VERSION 5.7 ;
  NOWIREEXTENSIONATPIN ON ;
  DIVIDERCHAR "/" ;
  BUSBITCHARS "[]" ;
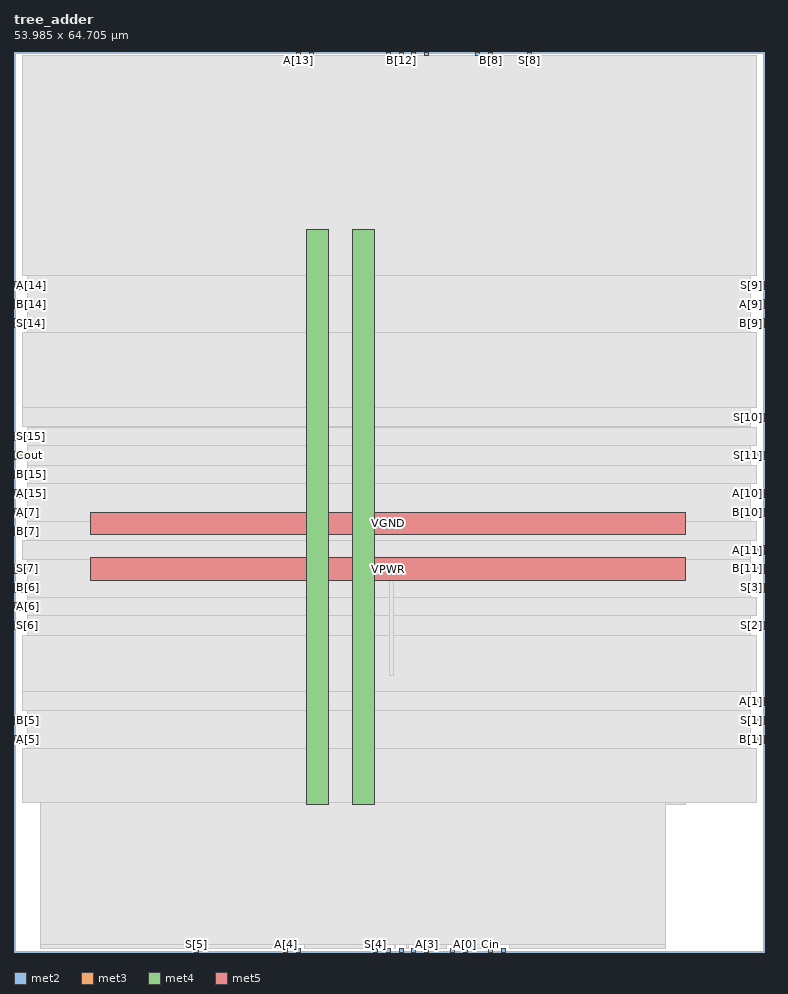
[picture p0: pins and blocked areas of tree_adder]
MACRO tree_adder
  CLASS BLOCK ;
  FOREIGN tree_adder ;
  ORIGIN 0.000 0.000 ;
  SIZE 53.985 BY 64.705 ;
  PIN A[0]
    DIRECTION INPUT ;
    USE SIGNAL ;
    ANTENNAGATEAREA 0.213000 ;
    PORT
      LAYER met2 ;
        RECT 32.290 0.000 32.570 0.280 ;
    END
  END A[0]
  PIN A[10]
    DIRECTION INPUT ;
    USE SIGNAL ;
    ANTENNAGATEAREA 0.213000 ;
    PORT
      LAYER met3 ;
        RECT 53.385 32.680 53.985 33.280 ;
    END
  END A[10]
  PIN A[11]
    DIRECTION INPUT ;
    USE SIGNAL ;
    ANTENNAGATEAREA 0.213000 ;
    PORT
      LAYER met3 ;
        RECT 53.385 28.600 53.985 29.200 ;
    END
  END A[11]
  PIN A[12]
    DIRECTION INPUT ;
    USE SIGNAL ;
    ANTENNAGATEAREA 0.213000 ;
    PORT
      LAYER met2 ;
        RECT 28.610 64.425 28.890 64.705 ;
    END
  END A[12]
  PIN A[13]
    DIRECTION INPUT ;
    USE SIGNAL ;
    ANTENNAGATEAREA 0.213000 ;
    PORT
      LAYER met2 ;
        RECT 20.330 64.425 20.610 64.705 ;
    END
  END A[13]
  PIN A[14]
    DIRECTION INPUT ;
    USE SIGNAL ;
    ANTENNAGATEAREA 0.213000 ;
    PORT
      LAYER met3 ;
        RECT 0.000 47.640 0.600 48.240 ;
    END
  END A[14]
  PIN A[15]
    DIRECTION INPUT ;
    USE SIGNAL ;
    ANTENNAGATEAREA 0.213000 ;
    PORT
      LAYER met3 ;
        RECT 0.000 32.680 0.600 33.280 ;
    END
  END A[15]
  PIN A[1]
    DIRECTION INPUT ;
    USE SIGNAL ;
    ANTENNAGATEAREA 0.213000 ;
    PORT
      LAYER met3 ;
        RECT 53.385 17.720 53.985 18.320 ;
    END
  END A[1]
  PIN A[2]
    DIRECTION INPUT ;
    USE SIGNAL ;
    ANTENNAGATEAREA 0.213000 ;
    PORT
      LAYER met2 ;
        RECT 26.770 0.000 27.050 0.280 ;
    END
  END A[2]
  PIN A[3]
    DIRECTION INPUT ;
    USE SIGNAL ;
    ANTENNAGATEAREA 0.213000 ;
    PORT
      LAYER met2 ;
        RECT 29.530 0.000 29.810 0.280 ;
    END
  END A[3]
  PIN A[4]
    DIRECTION INPUT ;
    USE SIGNAL ;
    ANTENNAGATEAREA 0.213000 ;
    PORT
      LAYER met2 ;
        RECT 19.410 0.000 19.690 0.280 ;
    END
  END A[4]
  PIN A[5]
    DIRECTION INPUT ;
    USE SIGNAL ;
    ANTENNAGATEAREA 0.213000 ;
    PORT
      LAYER met3 ;
        RECT 0.000 15.000 0.600 15.600 ;
    END
  END A[5]
  PIN A[6]
    DIRECTION INPUT ;
    USE SIGNAL ;
    ANTENNAGATEAREA 0.213000 ;
    PORT
      LAYER met3 ;
        RECT 0.000 24.520 0.600 25.120 ;
    END
  END A[6]
  PIN A[7]
    DIRECTION INPUT ;
    USE SIGNAL ;
    ANTENNAGATEAREA 0.213000 ;
    PORT
      LAYER met3 ;
        RECT 0.000 31.320 0.600 31.920 ;
    END
  END A[7]
  PIN A[8]
    DIRECTION INPUT ;
    USE SIGNAL ;
    ANTENNAGATEAREA 0.213000 ;
    PORT
      LAYER met2 ;
        RECT 33.210 64.425 33.490 64.705 ;
    END
  END A[8]
  PIN A[9]
    DIRECTION INPUT ;
    USE SIGNAL ;
    ANTENNAGATEAREA 0.213000 ;
    PORT
      LAYER met3 ;
        RECT 53.385 46.280 53.985 46.880 ;
    END
  END A[9]
  PIN B[0]
    DIRECTION INPUT ;
    USE SIGNAL ;
    ANTENNAGATEAREA 0.213000 ;
    PORT
      LAYER met2 ;
        RECT 31.370 0.000 31.650 0.280 ;
    END
  END B[0]
  PIN B[10]
    DIRECTION INPUT ;
    USE SIGNAL ;
    ANTENNAGATEAREA 0.213000 ;
    PORT
      LAYER met3 ;
        RECT 53.385 31.320 53.985 31.920 ;
    END
  END B[10]
  PIN B[11]
    DIRECTION INPUT ;
    USE SIGNAL ;
    ANTENNAGATEAREA 0.213000 ;
    PORT
      LAYER met3 ;
        RECT 53.385 27.240 53.985 27.840 ;
    END
  END B[11]
  PIN B[12]
    DIRECTION INPUT ;
    USE SIGNAL ;
    ANTENNAGATEAREA 0.213000 ;
    PORT
      LAYER met2 ;
        RECT 27.690 64.425 27.970 64.705 ;
    END
  END B[12]
  PIN B[13]
    DIRECTION INPUT ;
    USE SIGNAL ;
    ANTENNAGATEAREA 0.213000 ;
    PORT
      LAYER met2 ;
        RECT 21.250 64.400 21.530 64.705 ;
    END
  END B[13]
  PIN B[14]
    DIRECTION INPUT ;
    USE SIGNAL ;
    ANTENNAGATEAREA 0.213000 ;
    PORT
      LAYER met3 ;
        RECT 0.000 46.280 0.600 46.880 ;
    END
  END B[14]
  PIN B[15]
    DIRECTION INPUT ;
    USE SIGNAL ;
    ANTENNAGATEAREA 0.213000 ;
    PORT
      LAYER met3 ;
        RECT 0.000 34.040 0.600 34.640 ;
    END
  END B[15]
  PIN B[1]
    DIRECTION INPUT ;
    USE SIGNAL ;
    ANTENNAGATEAREA 0.213000 ;
    PORT
      LAYER met3 ;
        RECT 53.385 15.000 53.985 15.600 ;
    END
  END B[1]
  PIN B[2]
    DIRECTION INPUT ;
    USE SIGNAL ;
    ANTENNAGATEAREA 0.213000 ;
    PORT
      LAYER met2 ;
        RECT 27.690 0.000 27.970 0.280 ;
    END
  END B[2]
  PIN B[3]
    DIRECTION INPUT ;
    USE SIGNAL ;
    ANTENNAGATEAREA 0.213000 ;
    PORT
      LAYER met2 ;
        RECT 28.610 0.000 28.890 0.280 ;
    END
  END B[3]
  PIN B[4]
    DIRECTION INPUT ;
    USE SIGNAL ;
    ANTENNAGATEAREA 0.213000 ;
    PORT
      LAYER met2 ;
        RECT 20.330 0.000 20.610 0.280 ;
    END
  END B[4]
  PIN B[5]
    DIRECTION INPUT ;
    USE SIGNAL ;
    ANTENNAGATEAREA 0.213000 ;
    PORT
      LAYER met3 ;
        RECT 0.000 16.360 0.600 16.960 ;
    END
  END B[5]
  PIN B[6]
    DIRECTION INPUT ;
    USE SIGNAL ;
    ANTENNAGATEAREA 0.213000 ;
    PORT
      LAYER met3 ;
        RECT 0.000 25.880 0.600 26.480 ;
    END
  END B[6]
  PIN B[7]
    DIRECTION INPUT ;
    USE SIGNAL ;
    ANTENNAGATEAREA 0.213000 ;
    PORT
      LAYER met3 ;
        RECT 0.000 29.960 0.600 30.560 ;
    END
  END B[7]
  PIN B[8]
    DIRECTION INPUT ;
    USE SIGNAL ;
    ANTENNAGATEAREA 0.213000 ;
    PORT
      LAYER met2 ;
        RECT 34.130 64.425 34.410 64.705 ;
    END
  END B[8]
  PIN B[9]
    DIRECTION INPUT ;
    USE SIGNAL ;
    ANTENNAGATEAREA 0.213000 ;
    PORT
      LAYER met3 ;
        RECT 53.385 44.920 53.985 45.520 ;
    END
  END B[9]
  PIN Cin
    DIRECTION INPUT ;
    USE SIGNAL ;
    ANTENNAGATEAREA 0.213000 ;
    PORT
      LAYER met2 ;
        RECT 34.130 0.000 34.410 0.280 ;
    END
  END Cin
  PIN Cout
    DIRECTION OUTPUT ;
    USE SIGNAL ;
    ANTENNAGATEAREA 0.126000 ;
    ANTENNADIFFAREA 0.429000 ;
    PORT
      LAYER met3 ;
        RECT 0.000 35.400 0.600 36.000 ;
    END
  END Cout
  PIN S[0]
    DIRECTION OUTPUT ;
    USE SIGNAL ;
    ANTENNADIFFAREA 0.702900 ;
    PORT
      LAYER met2 ;
        RECT 35.050 0.000 35.330 0.280 ;
    END
  END S[0]
  PIN S[10]
    DIRECTION OUTPUT ;
    USE SIGNAL ;
    ANTENNADIFFAREA 0.702900 ;
    PORT
      LAYER met3 ;
        RECT 53.385 38.120 53.985 38.720 ;
    END
  END S[10]
  PIN S[11]
    DIRECTION OUTPUT ;
    USE SIGNAL ;
    ANTENNADIFFAREA 0.383400 ;
    PORT
      LAYER met3 ;
        RECT 53.385 35.400 53.985 36.000 ;
    END
  END S[11]
  PIN S[12]
    DIRECTION OUTPUT ;
    USE SIGNAL ;
    ANTENNADIFFAREA 0.702900 ;
    PORT
      LAYER met2 ;
        RECT 26.770 64.425 27.050 64.705 ;
    END
  END S[12]
  PIN S[13]
    DIRECTION OUTPUT ;
    USE SIGNAL ;
    ANTENNAGATEAREA 0.126000 ;
    ANTENNADIFFAREA 0.429000 ;
    PORT
      LAYER met2 ;
        RECT 29.530 64.425 29.810 64.705 ;
    END
  END S[13]
  PIN S[14]
    DIRECTION OUTPUT ;
    USE SIGNAL ;
    ANTENNAGATEAREA 0.126000 ;
    ANTENNADIFFAREA 0.429000 ;
    PORT
      LAYER met3 ;
        RECT 0.000 44.920 0.600 45.520 ;
    END
  END S[14]
  PIN S[15]
    DIRECTION OUTPUT ;
    USE SIGNAL ;
    ANTENNAGATEAREA 0.126000 ;
    ANTENNADIFFAREA 0.429000 ;
    PORT
      LAYER met3 ;
        RECT 0.000 36.760 0.600 37.360 ;
    END
  END S[15]
  PIN S[1]
    DIRECTION OUTPUT ;
    USE SIGNAL ;
    ANTENNADIFFAREA 0.702900 ;
    PORT
      LAYER met3 ;
        RECT 53.385 16.360 53.985 16.960 ;
    END
  END S[1]
  PIN S[2]
    DIRECTION OUTPUT ;
    USE SIGNAL ;
    ANTENNADIFFAREA 0.702900 ;
    PORT
      LAYER met3 ;
        RECT 53.385 23.160 53.985 23.760 ;
    END
  END S[2]
  PIN S[3]
    DIRECTION OUTPUT ;
    USE SIGNAL ;
    ANTENNADIFFAREA 0.702900 ;
    PORT
      LAYER met3 ;
        RECT 53.385 25.880 53.985 26.480 ;
    END
  END S[3]
  PIN S[4]
    DIRECTION OUTPUT ;
    USE SIGNAL ;
    ANTENNADIFFAREA 0.702900 ;
    PORT
      LAYER met2 ;
        RECT 25.850 0.000 26.130 0.280 ;
    END
  END S[4]
  PIN S[5]
    DIRECTION OUTPUT ;
    USE SIGNAL ;
    ANTENNADIFFAREA 0.702900 ;
    PORT
      LAYER met2 ;
        RECT 12.970 0.000 13.250 0.280 ;
    END
  END S[5]
  PIN S[6]
    DIRECTION OUTPUT ;
    USE SIGNAL ;
    ANTENNADIFFAREA 0.702900 ;
    PORT
      LAYER met3 ;
        RECT 0.000 23.160 0.600 23.760 ;
    END
  END S[6]
  PIN S[7]
    DIRECTION OUTPUT ;
    USE SIGNAL ;
    ANTENNADIFFAREA 0.702900 ;
    PORT
      LAYER met3 ;
        RECT 0.000 27.240 0.600 27.840 ;
    END
  END S[7]
  PIN S[8]
    DIRECTION OUTPUT ;
    USE SIGNAL ;
    ANTENNADIFFAREA 0.702900 ;
    PORT
      LAYER met2 ;
        RECT 36.890 64.425 37.170 64.705 ;
    END
  END S[8]
  PIN S[9]
    DIRECTION OUTPUT ;
    USE SIGNAL ;
    ANTENNADIFFAREA 0.702900 ;
    PORT
      LAYER met3 ;
        RECT 53.385 47.640 53.985 48.240 ;
    END
  END S[9]
  PIN VGND
    DIRECTION INOUT ;
    USE GROUND ;
    PORT
      LAYER met4 ;
        RECT 24.340 10.640 25.940 51.920 ;
    END
    PORT
      LAYER met5 ;
        RECT 5.520 30.030 48.300 31.630 ;
    END
  END VGND
  PIN VPWR
    DIRECTION INOUT ;
    USE POWER ;
    PORT
      LAYER met4 ;
        RECT 21.040 10.640 22.640 51.920 ;
    END
    PORT
      LAYER met5 ;
        RECT 5.520 26.730 48.300 28.330 ;
    END
  END VPWR
  OBS
      LAYER nwell ;
        RECT 5.330 10.795 48.490 51.870 ;
      LAYER li1 ;
        RECT 5.520 10.795 48.300 51.765 ;
      LAYER met1 ;
        RECT 1.910 10.640 48.300 51.920 ;
      LAYER met2 ;
        RECT 1.930 64.145 20.050 64.445 ;
        RECT 20.890 64.145 20.970 64.445 ;
        RECT 1.930 64.120 20.970 64.145 ;
        RECT 21.810 64.145 26.490 64.445 ;
        RECT 27.330 64.145 27.410 64.445 ;
        RECT 28.250 64.145 28.330 64.445 ;
        RECT 29.170 64.145 29.250 64.445 ;
        RECT 30.090 64.145 32.930 64.445 ;
        RECT 33.770 64.145 33.850 64.445 ;
        RECT 34.690 64.145 36.610 64.445 ;
        RECT 37.450 64.145 46.830 64.445 ;
        RECT 21.810 64.120 46.830 64.145 ;
        RECT 1.930 0.560 46.830 64.120 ;
        RECT 1.930 0.280 12.690 0.560 ;
        RECT 13.530 0.280 19.130 0.560 ;
        RECT 19.970 0.280 20.050 0.560 ;
        RECT 20.890 0.280 25.570 0.560 ;
        RECT 26.410 0.280 26.490 0.560 ;
        RECT 27.330 0.280 27.410 0.560 ;
        RECT 28.250 0.280 28.330 0.560 ;
        RECT 29.170 0.280 29.250 0.560 ;
        RECT 30.090 0.280 31.090 0.560 ;
        RECT 31.930 0.280 32.010 0.560 ;
        RECT 32.850 0.280 33.850 0.560 ;
        RECT 34.690 0.280 34.770 0.560 ;
        RECT 35.610 0.280 46.830 0.560 ;
      LAYER met3 ;
        RECT 0.600 48.640 53.385 64.425 ;
        RECT 1.000 44.520 52.985 48.640 ;
        RECT 0.600 39.120 53.385 44.520 ;
        RECT 0.600 37.760 52.985 39.120 ;
        RECT 1.000 37.720 52.985 37.760 ;
        RECT 1.000 36.400 53.385 37.720 ;
        RECT 1.000 35.000 52.985 36.400 ;
        RECT 1.000 33.680 53.385 35.000 ;
        RECT 1.000 30.920 52.985 33.680 ;
        RECT 1.000 29.600 53.385 30.920 ;
        RECT 1.000 29.560 52.985 29.600 ;
        RECT 0.600 28.240 52.985 29.560 ;
        RECT 1.000 25.480 52.985 28.240 ;
        RECT 1.000 24.160 53.385 25.480 ;
        RECT 1.000 22.760 52.985 24.160 ;
        RECT 0.600 18.720 53.385 22.760 ;
        RECT 0.600 17.360 52.985 18.720 ;
        RECT 1.000 14.600 52.985 17.360 ;
        RECT 0.600 10.715 53.385 14.600 ;
      LAYER met4 ;
        RECT 26.975 19.895 27.305 28.385 ;
  END
END tree_adder
END LIBRARY

